VERSION 5.7 ;
  NOWIREEXTENSIONATPIN ON ;
  DIVIDERCHAR "/" ;
  BUSBITCHARS "[]" ;
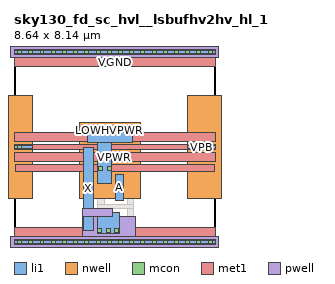
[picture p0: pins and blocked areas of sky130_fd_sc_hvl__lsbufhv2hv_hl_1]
MACRO sky130_fd_sc_hvl__lsbufhv2hv_hl_1
  CLASS BLOCK ;
  FOREIGN sky130_fd_sc_hvl__lsbufhv2hv_hl_1 ;
  ORIGIN 0.000 0.000 ;
  SIZE 8.640 BY 8.140 ;
  PIN A
    ANTENNAGATEAREA 0.585000 ;
    PORT
      LAYER li1 ;
        RECT 4.355 1.775 4.685 2.900 ;
    END
  END A
  PIN LOWHVPWR
    ANTENNADIFFAREA 1.512150 ;
    PORT
      LAYER nwell ;
        RECT 2.800 1.885 5.425 5.135 ;
      LAYER li1 ;
        RECT 3.130 4.265 5.095 4.835 ;
        RECT 3.565 2.485 4.185 4.265 ;
      LAYER mcon ;
        RECT 3.630 3.075 3.800 3.245 ;
        RECT 3.990 3.075 4.160 3.245 ;
      LAYER met1 ;
        RECT 0.070 3.020 8.570 3.305 ;
    END
  END LOWHVPWR
  PIN VGND
    USE GROUND ;
    PORT
      LAYER met1 ;
        RECT 0.000 7.515 8.640 7.885 ;
    END
    PORT
      LAYER li1 ;
        RECT 3.565 0.365 4.515 1.265 ;
      LAYER mcon ;
        RECT 3.595 0.395 3.765 0.565 ;
        RECT 3.955 0.395 4.125 0.565 ;
        RECT 4.315 0.395 4.485 0.565 ;
      LAYER met1 ;
        RECT 0.000 0.255 8.640 0.625 ;
    END
  END VGND
  PIN VNB
    ANTENNADIFFAREA 1.468800 ;
    PORT
      LAYER pwell ;
        RECT 2.915 1.085 4.225 1.415 ;
        RECT 2.915 0.215 5.225 1.085 ;
        RECT -0.130 -0.215 8.770 0.215 ;
      LAYER li1 ;
        RECT 0.000 -0.085 8.640 0.085 ;
      LAYER mcon ;
        RECT 0.155 -0.085 0.325 0.085 ;
        RECT 0.635 -0.085 0.805 0.085 ;
        RECT 1.115 -0.085 1.285 0.085 ;
        RECT 1.595 -0.085 1.765 0.085 ;
        RECT 2.075 -0.085 2.245 0.085 ;
        RECT 2.555 -0.085 2.725 0.085 ;
        RECT 3.035 -0.085 3.205 0.085 ;
        RECT 3.515 -0.085 3.685 0.085 ;
        RECT 3.995 -0.085 4.165 0.085 ;
        RECT 4.475 -0.085 4.645 0.085 ;
        RECT 4.955 -0.085 5.125 0.085 ;
        RECT 5.435 -0.085 5.605 0.085 ;
        RECT 5.915 -0.085 6.085 0.085 ;
        RECT 6.395 -0.085 6.565 0.085 ;
        RECT 6.875 -0.085 7.045 0.085 ;
        RECT 7.355 -0.085 7.525 0.085 ;
        RECT 7.835 -0.085 8.005 0.085 ;
        RECT 8.315 -0.085 8.485 0.085 ;
      LAYER met1 ;
        RECT 0.000 -0.115 8.640 0.115 ;
    END
    PORT
      LAYER pwell ;
        RECT -0.130 7.925 8.770 8.355 ;
      LAYER li1 ;
        RECT 0.000 8.055 8.640 8.225 ;
      LAYER mcon ;
        RECT 0.155 8.055 0.325 8.225 ;
        RECT 0.635 8.055 0.805 8.225 ;
        RECT 1.115 8.055 1.285 8.225 ;
        RECT 1.595 8.055 1.765 8.225 ;
        RECT 2.075 8.055 2.245 8.225 ;
        RECT 2.555 8.055 2.725 8.225 ;
        RECT 3.035 8.055 3.205 8.225 ;
        RECT 3.515 8.055 3.685 8.225 ;
        RECT 3.995 8.055 4.165 8.225 ;
        RECT 4.475 8.055 4.645 8.225 ;
        RECT 4.955 8.055 5.125 8.225 ;
        RECT 5.435 8.055 5.605 8.225 ;
        RECT 5.915 8.055 6.085 8.225 ;
        RECT 6.395 8.055 6.565 8.225 ;
        RECT 6.875 8.055 7.045 8.225 ;
        RECT 7.355 8.055 7.525 8.225 ;
        RECT 7.835 8.055 8.005 8.225 ;
        RECT 8.315 8.055 8.485 8.225 ;
      LAYER met1 ;
        RECT 0.000 8.025 8.640 8.255 ;
    END
  END VNB
  PIN VPB
    ANTENNADIFFAREA 0.230350 ;
    PORT
      LAYER nwell ;
        RECT -0.330 1.885 0.800 6.255 ;
        RECT 7.425 1.885 8.970 6.255 ;
      LAYER li1 ;
        RECT 0.000 3.985 0.800 4.155 ;
        RECT 7.425 3.985 8.640 4.155 ;
      LAYER mcon ;
        RECT 0.155 3.985 0.325 4.155 ;
        RECT 7.835 3.985 8.005 4.155 ;
        RECT 8.315 3.985 8.485 4.155 ;
      LAYER met1 ;
        RECT 0.000 3.955 8.640 4.185 ;
    END
  END VPB
  PIN VPWR
    USE POWER ;
    PORT
      LAYER met1 ;
        RECT 0.000 3.445 8.640 3.815 ;
    END
    PORT
      LAYER met1 ;
        RECT 0.000 4.325 8.640 4.695 ;
    END
  END VPWR
  PIN X
    ANTENNADIFFAREA 0.626250 ;
    PORT
      LAYER li1 ;
        RECT 2.995 0.495 3.395 4.065 ;
    END
  END X
  OBS
      LAYER li1 ;
        RECT 3.565 1.605 3.895 2.065 ;
        RECT 4.865 1.605 5.115 3.315 ;
        RECT 3.565 1.435 5.115 1.605 ;
        RECT 4.865 0.495 5.115 1.435 ;
  END
END sky130_fd_sc_hvl__lsbufhv2hv_hl_1
END LIBRARY

